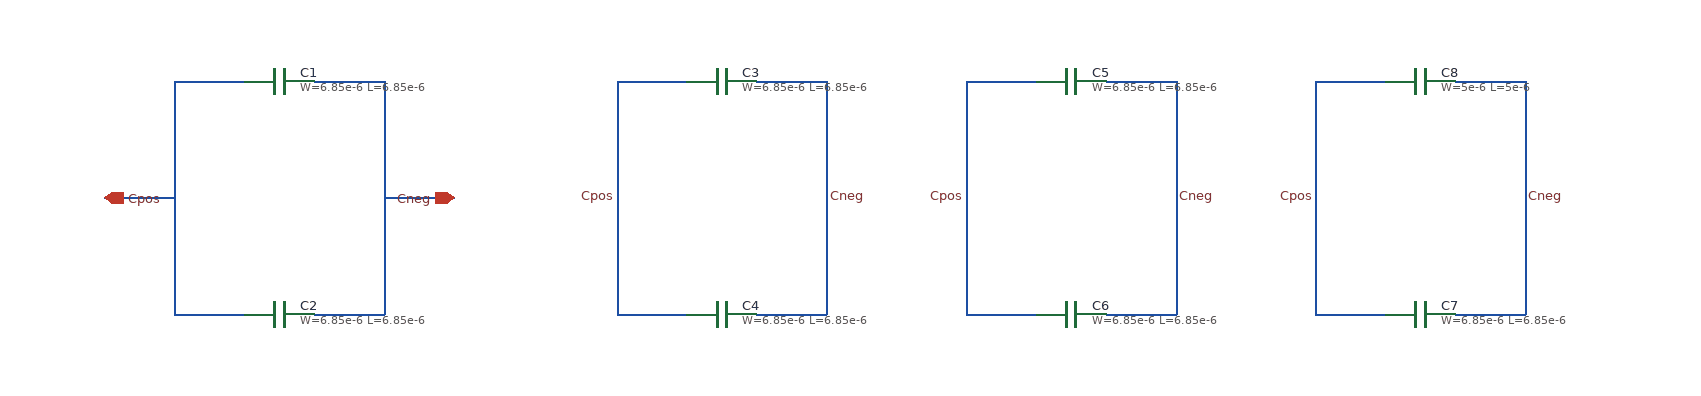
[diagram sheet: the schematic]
v {xschem version=3.4.8RC file_version=1.3}
G {}
K {}
V {}
S {}
F {}
E {}
N 720 -460 780 -460 {lab=Cneg}
N 600 -460 660 -460 {lab=Cpos}
N 600 -260 660 -260 {lab=Cpos}
N 720 -260 780 -260 {lab=Cneg}
N 340 -460 400 -460 {lab=Cneg}
N 220 -460 280 -460 {lab=Cpos}
N 220 -260 280 -260 {lab=Cpos}
N 340 -260 400 -260 {lab=Cneg}
N 400 -460 400 -260 {lab=Cneg}
N 220 -460 220 -260 {lab=Cpos}
N 160 -360 220 -360 {lab=Cpos}
N 400 -360 460 -360 {lab=Cneg}
N 600 -460 600 -260 {lab=Cpos}
N 780 -460 780 -260 {lab=Cneg}
N 1020 -460 1080 -460 {lab=Cneg}
N 900 -460 960 -460 {lab=Cpos}
N 900 -260 960 -260 {lab=Cpos}
N 1020 -260 1080 -260 {lab=Cneg}
N 900 -460 900 -260 {lab=Cpos}
N 1080 -460 1080 -260 {lab=Cneg}
N 1320 -460 1380 -460 {lab=Cneg}
N 1200 -460 1260 -460 {lab=Cpos}
N 1200 -260 1260 -260 {lab=Cpos}
N 1320 -260 1380 -260 {lab=Cneg}
N 1200 -460 1200 -260 {lab=Cpos}
N 1380 -460 1380 -260 {lab=Cneg}
C {iopin.sym} 160 -360 0 1 {name=p3 lab=Cpos}
C {iopin.sym} 460 -360 0 0 {name=p4 lab=Cneg}
C {lab_pin.sym} 600 -360 0 0 {name=p20 lab=Cpos}
C {lab_pin.sym} 780 -360 0 1 {name=p5 lab=Cneg}
C {lab_pin.sym} 900 -360 0 0 {name=p1 lab=Cpos}
C {lab_pin.sym} 1080 -360 0 1 {name=p2 lab=Cneg}
C {lab_pin.sym} 1200 -360 0 0 {name=p6 lab=Cpos}
C {lab_pin.sym} 1380 -360 0 1 {name=p7 lab=Cneg}
C {symbols/cap_mim_2f0fF.sym} 310 -460 3 0 {name=C1
W=6.85e-6
L=6.85e-6
model=cap_mim_2f0fF
spiceprefix=X
m=1}
C {symbols/cap_mim_2f0fF.sym} 310 -260 3 1 {name=C2
W=6.85e-6
L=6.85e-6
model=cap_mim_2f0fF
spiceprefix=X
m=1}
C {symbols/cap_mim_2f0fF.sym} 690 -460 3 0 {name=C3
W=6.85e-6
L=6.85e-6
model=cap_mim_2f0fF
spiceprefix=X
m=1}
C {symbols/cap_mim_2f0fF.sym} 690 -260 3 1 {name=C4
W=6.85e-6
L=6.85e-6
model=cap_mim_2f0fF
spiceprefix=X
m=1}
C {symbols/cap_mim_2f0fF.sym} 990 -460 3 0 {name=C5
W=6.85e-6
L=6.85e-6
model=cap_mim_2f0fF
spiceprefix=X
m=1}
C {symbols/cap_mim_2f0fF.sym} 990 -260 3 1 {name=C6
W=6.85e-6
L=6.85e-6
model=cap_mim_2f0fF
spiceprefix=X
m=1}
C {symbols/cap_mim_2f0fF.sym} 1290 -260 3 1 {name=C7
W=6.85e-6
L=6.85e-6
model=cap_mim_2f0fF
spiceprefix=X
m=1}
C {symbols/cap_mim_2f0fF.sym} 1290 -460 3 0 {name=C8
W=5e-6
L=5e-6
model=cap_mim_2f0fF
spiceprefix=X
m=1}
C {title.sym} 220 -80 0 0 {name=l1 author="Sayyad Arif"}
